VERSION 5.7 ;
  NOWIREEXTENSIONATPIN ON ;
  DIVIDERCHAR "/" ;
  BUSBITCHARS "[]" ;
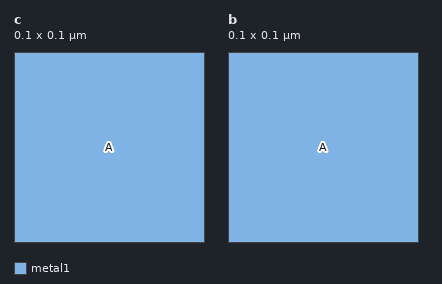
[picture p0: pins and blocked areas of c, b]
MACRO c
  CLASS BLOCK ;
  FOREIGN c ;
  ORIGIN 0.000 0.000 ;
  SIZE 0.100 BY 0.100 ;
  PIN A
    PORT
      LAYER metal1 ;
        RECT 0.000 0.000 0.100 0.100 ;
    END
  END A
END c
MACRO a
  CLASS BLOCK ;
  FOREIGN a ;
  ORIGIN 0.000 0.000 ;
  SIZE 0.300 BY 0.100 ;
  OBS
      LAYER metal1 ;
        RECT 0.200 0.000 0.300 0.100 ;
      LAYER metal2 ;
        RECT 0.000 0.000 0.050 0.050 ;
  END
END a
MACRO b
  CLASS BLOCK ;
  FOREIGN b ;
  ORIGIN 0.000 0.000 ;
  SIZE 0.100 BY 0.100 ;
  PIN A
    PORT
      LAYER metal1 ;
        RECT 0.000 0.000 0.100 0.100 ;
    END
  END A
END b
END LIBRARY

